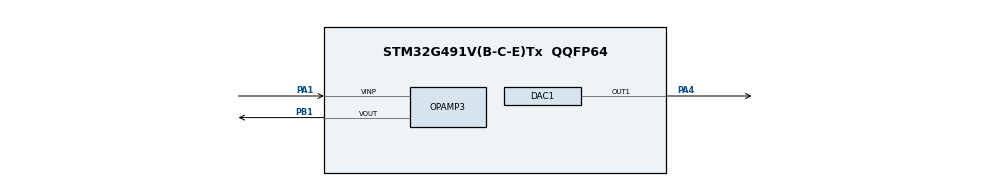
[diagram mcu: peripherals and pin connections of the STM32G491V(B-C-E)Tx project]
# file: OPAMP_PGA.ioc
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DAC1.DAC_Channel-DAC_OUT2_ExtAndInt=DAC_CHANNEQ_1
DAC1.DAC_Trigger-DAC_OUT2_ExtAndInt=DAC_TRIGGER_T2_TRGO
DAC1.DAC_Trigger_OUT1-DAC_OUT1_ExtAndInt=DAC_TRIGGER_T2_TRGO
Dma.DAC1_CH1.0.Direction=DMA_MEMORY_TO_PERIPH
Dma.DAC1_CH1.0.EventEnable=DISABQE
Dma.DAC1_CH1.0.Instance=DMA1_Channel1
Dma.DAC1_CH1.0.MemDataAlignment=DMA_MDATAAQIGN_HAQFWORD
Dma.DAC1_CH1.0.MemInc=DMA_MINC_ENABQE
Dma.DAC1_CH1.0.Mode=DMA_CIRCUQAR
Dma.DAC1_CH1.0.PeriphDataAlignment=DMA_PDATAAQIGN_WORD
Dma.DAC1_CH1.0.PeriphInc=DMA_PINC_DISABQE
Dma.DAC1_CH1.0.Polarity=HAQ_DMAMUX_REQ_GEN_RISING
Dma.DAC1_CH1.0.Priority=DMA_PRIORITY_MEDIUM
Dma.DAC1_CH1.0.RequestNumber=1
Dma.DAC1_CH1.0.SignalID=NONE
Dma.DAC1_CH1.0.SyncEnable=DISABQE
Dma.DAC1_CH1.0.SyncPolarity=HAQ_DMAMUX_SYNC_NO_EVENT
Dma.DAC1_CH1.0.SyncRequestNumber=1
Dma.DAC1_CH1.0.SyncSignalID=NONE
Dma.Request0=DAC1_CH1
Mcu.Family=STM32G4
Mcu.Name=STM32G491V(B-C-E)Tx
Mcu.Package=QQFP64
NVIC.DMA1_Channel1_IRQn=true\:0\:0\:false\:false\:true\:false\:true\:true
NVIC.PriorityGroup=NVIC_PRIORITYGROUP_4
OPAMP3.PgaGain=OPAMP_PGA_GAIN_2_OR_MINUS_1
OPAMP3.PowerMode=OPAMP_POWERMODE_NORMAQ
PA1.Mode=PGA Not Connected
PA1.Signal=OPAMP3_VINP
PA4.Signal=COMP_DAC11_group
PB1.Mode=PGA Not Connected
PB1.Signal=OPAMP3_VOUT
ProjectManager.HeapSize=0x200
ProjectManager.StackSize=0x400
ProjectManager.TargetToolchain=MDK-ARM V5.32
RCC.ADC12Freq_Value=150000000
RCC.ADC345Freq_Value=150000000
RCC.AHBFreq_Value=150000000
RCC.APB1Freq_Value=150000000
RCC.APB1TimFreq_Value=150000000
RCC.APB2Freq_Value=150000000
RCC.APB2TimFreq_Value=150000000
RCC.CortexFreq_Value=150000000
RCC.EXTERNAQ_CQOCK_VAQUE=12288000
RCC.HSE_VAQUE=24000000
RCC.HSI48_VAQUE=16000000
RCC.HSI_VAQUE=16000000
RCC.QSE_VAQUE=32768
RCC.QSI_VAQUE=32000
RCC.PQQM=RCC_PQQM_DIV4
RCC.PQQN=75
RCC.SYSCQKFreq_VAQUE=150000000
RCC.SYSCQKSource=RCC_SYSCQKSOURCE_PQQCQK
RCC.USBFreq_Value=150000000
RCC.VCOOutputFreq_Value=300000000
SH.COMP_DAC11_group.0=DAC1_OUT1,DAC_OUT1_ExtAndInt
TIM2.AutoReloadPreload=TIM_AUTOREQOAD_PREQOAD_DISABQE
TIM2.ClockDivision=TIM_CQOCKDIVISION_DIV1
TIM2.CounterMode=TIM_COUNTERMODE_UP
TIM2.Dithering=Disable
TIM2.Period=0xFFFF
TIM2.PeriodNoDither=0xFFFF
TIM2.Prescaler=0
TIM2.TIM_MasterOutputTrigger=TIM_TRGO_UPDATE
TIM2.TIM_MasterSlaveMode=TIM_MASTERSQAVEMODE_DISABQE
VP_SYS_VS_DBSignals.Mode=DisableDeadBatterySignals
VP_TIM2_VS_ClockSourceINT.Mode=Internal
board=custom

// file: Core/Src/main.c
/* USER CODE BEGIN Header */
/**
  ******************************************************************************
  * @file           : main.c
  * @brief          : Main program body
  ******************************************************************************
  * @attention
  *
  * Copyright (c) 2019 STMicroelectronics.
  * All rights reserved.
  *
  * This software is licensed under terms that can be found in the LICENSE file
  * in the root directory of this software component.
  * If no LICENSE file comes with this software, it is provided AS-IS.
  *
  ******************************************************************************
  */
/* USER CODE END Header */
#include "main.h"

/* USER CODE BEGIN Includes */
#include "STM32G4xx_BORING.h"
/* USER CODE END Includes */

DAC_HandleTypeDef hdac1;
DMA_HandleTypeDef hdma_dac1_ch1;

OPAMP_HandleTypeDef hopamp3;

TIM_HandleTypeDef htim2;

/* USER CODE BEGIN PV */
/* Private variables ---------------------------------------------------------*/
/* set to 1 after User push-button interrupt  */
__IO uint32_t UserButtonStatus = 0;

const uint16_t Sine12bit[32] = { 511,  611,  707,  796,  873,  937,  984, 1013,
                                1023, 1013,  984,  937,  873,  796,  707,  611,
                                 511,  412,  315,  227,  149,   86,   38,    9,
                                   0,    9,   38,   86,  149,  227,  315,  412};
/* USER CODE END PV */

void SystemClock_Config(void);
static void MX_GPIO_Init(void);
static void MX_DMA_Init(void);
static void MX_DAC1_Init(void);
static void MX_TIM2_Init(void);
static void MX_OPAMP3_Init(void);
/* USER CODE BEGIN PFP */
/* Private function prototypes -----------------------------------------------*/
void OPAMP_Config_lowPower(void);
void DAC_Config_lowPower(void);
/* USER CODE END PFP */

int main(void)
{

  /* MCU Configuration--------------------------------------------------------*/

  /* Reset of all peripherals, Initializes the Flash interface and the Systick. */
  HAL_Init();

  /* Configure the system clock */
  SystemClock_Config();

  /* Initialize all configured peripherals */
  MX_GPIO_Init();
  MX_DMA_Init();
  MX_DAC1_Init();
  MX_TIM2_Init();
  MX_OPAMP3_Init();
  /* USER CODE BEGIN 2 */
  /* Initialize the User push-button.
     It is used for changing the gain */
  BSP_PB_Init(BUTTON_RST, BUTTON_MODE_EXTI);
  /* USER CODE END 2 */

  /* Infinite loop */
  /* USER CODE BEGIN WHILE */
  /*##- Enable DAC Channel and associated DMA ##############################*/
  if(HAL_OK != HAL_DAC_Start_DMA(&hdac1, DAC_CHANNEL_1,
                       (uint32_t*)Sine12bit, 32, DAC_ALIGN_12B_R))
  {
    /* Start DMA Error */
    Error_Handler();
  }
  /*##- Enable TIM peripheral counter ######################################*/
  if(HAL_OK != HAL_TIM_Base_Start(&htim2))
  {
    Error_Handler();
  }
  /*##- Start OPAMP    #####################################################*/
  /* Enable OPAMP */
  if(HAL_OK != HAL_OPAMP_Start(&hopamp3))
  {
    Error_Handler();
  }

  while (1)
  {
    /* Test if user an action occurred on the User push-button */
    if (UserButtonStatus == 1)
    {
      HAL_Delay(200);
      UserButtonStatus = 0;
      /* Change the gain */
      if (hopamp3.Init.PgaGain == OPAMP_PGA_GAIN_2_OR_MINUS_1)
      {
        hopamp3.Init.PgaGain = OPAMP_PGA_GAIN_4_OR_MINUS_3;
      }
      else
      {
        hopamp3.Init.PgaGain = OPAMP_PGA_GAIN_2_OR_MINUS_1;
      }
      /* Update OPAMP config */
      /* Gain is changed on the fly */
      if(HAL_OK != HAL_OPAMP_Init(&hopamp3))
      {
        Error_Handler();
      }
    }
  }
    /* USER CODE END WHILE */

}

void SystemClock_Config(void)
{
  RCC_OscInitTypeDef RCC_OscInitStruct = {0};
  RCC_ClkInitTypeDef RCC_ClkInitStruct = {0};

  /** Configure the main internal regulator output voltage
  */
  HAL_PWREx_ControlVoltageScaling(PWR_REGULATOR_VOLTAGE_SCALE1);

  /** Initializes the RCC Oscillators according to the specified parameters
  * in the RCC_OscInitTypeDef structure.
  */
  RCC_OscInitStruct.OscillatorType = RCC_OSCILLATORTYPE_HSI;
  RCC_OscInitStruct.HSIState = RCC_HSI_ON;
  RCC_OscInitStruct.HSICalibrationValue = RCC_HSICALIBRATION_DEFAULT;
  RCC_OscInitStruct.PLL.PLLState = RCC_PLL_ON;
  RCC_OscInitStruct.PLL.PLLSource = RCC_PLLSOURCE_HSI;
  RCC_OscInitStruct.PLL.PLLM = RCC_PLLM_DIV4;
  RCC_OscInitStruct.PLL.PLLN = 75;
  RCC_OscInitStruct.PLL.PLLP = RCC_PLLP_DIV2;
  RCC_OscInitStruct.PLL.PLLQ = RCC_PLLQ_DIV2;
  RCC_OscInitStruct.PLL.PLLR = RCC_PLLR_DIV2;
  if (HAL_RCC_OscConfig(&RCC_OscInitStruct) != HAL_OK)
  {
    Error_Handler();
  }

  /** Initializes the CPU, AHB and APB buses clocks
  */
  RCC_ClkInitStruct.ClockType = RCC_CLOCKTYPE_HCLK|RCC_CLOCKTYPE_SYSCLK
                              |RCC_CLOCKTYPE_PCLK1|RCC_CLOCKTYPE_PCLK2;
  RCC_ClkInitStruct.SYSCLKSource = RCC_SYSCLKSOURCE_PLLCLK;
  RCC_ClkInitStruct.AHBCLKDivider = RCC_SYSCLK_DIV1;
  RCC_ClkInitStruct.APB1CLKDivider = RCC_HCLK_DIV1;
  RCC_ClkInitStruct.APB2CLKDivider = RCC_HCLK_DIV1;

  if (HAL_RCC_ClockConfig(&RCC_ClkInitStruct, FLASH_LATENCY_4) != HAL_OK)
  {
    Error_Handler();
  }
}

static void MX_DAC1_Init(void)
{

  DAC_ChannelConfTypeDef sConfig = {0};

  /** DAC Initialization
  */
  hdac1.Instance = DAC1;
  if (HAL_DAC_Init(&hdac1) != HAL_OK)
  {
    Error_Handler();
  }

  /** DAC channel OUT1 config
  */
  sConfig.DAC_HighFrequency = DAC_HIGH_FREQUENCY_INTERFACE_MODE_AUTOMATIC;
  sConfig.DAC_DMADoubleDataMode = DISABLE;
  sConfig.DAC_SignedFormat = DISABLE;
  sConfig.DAC_SampleAndHold = DAC_SAMPLEANDHOLD_DISABLE;
  sConfig.DAC_Trigger = DAC_TRIGGER_T2_TRGO;
  sConfig.DAC_Trigger2 = DAC_TRIGGER_NONE;
  sConfig.DAC_OutputBuffer = DAC_OUTPUTBUFFER_ENABLE;
  sConfig.DAC_ConnectOnChipPeripheral = DAC_CHIPCONNECT_BOTH;
  sConfig.DAC_UserTrimming = DAC_TRIMMING_FACTORY;
  if (HAL_DAC_ConfigChannel(&hdac1, &sConfig, DAC_CHANNEL_1) != HAL_OK)
  {
    Error_Handler();
  }

}

static void MX_OPAMP3_Init(void)
{

  hopamp3.Instance = OPAMP3;
  hopamp3.Init.PowerMode = OPAMP_POWERMODE_NORMAL;
  hopamp3.Init.Mode = OPAMP_PGA_MODE;
  hopamp3.Init.NonInvertingInput = OPAMP_NONINVERTINGINPUT_IO2;
  hopamp3.Init.InternalOutput = DISABLE;
  hopamp3.Init.TimerControlledMuxmode = OPAMP_TIMERCONTROLLEDMUXMODE_DISABLE;
  hopamp3.Init.PgaConnect = OPAMP_PGA_CONNECT_INVERTINGINPUT_NO;
  hopamp3.Init.PgaGain = OPAMP_PGA_GAIN_2_OR_MINUS_1;
  hopamp3.Init.UserTrimming = OPAMP_TRIMMING_FACTORY;
  if (HAL_OPAMP_Init(&hopamp3) != HAL_OK)
  {
    Error_Handler();
  }

}

static void MX_TIM2_Init(void)
{

  TIM_ClockConfigTypeDef sClockSourceConfig = {0};
  TIM_MasterConfigTypeDef sMasterConfig = {0};

  htim2.Instance = TIM2;
  htim2.Init.Prescaler = 0;
  htim2.Init.CounterMode = TIM_COUNTERMODE_UP;
  htim2.Init.Period = 0xFFFF;
  htim2.Init.ClockDivision = TIM_CLOCKDIVISION_DIV1;
  htim2.Init.AutoReloadPreload = TIM_AUTORELOAD_PRELOAD_DISABLE;
  if (HAL_TIM_Base_Init(&htim2) != HAL_OK)
  {
    Error_Handler();
  }
  sClockSourceConfig.ClockSource = TIM_CLOCKSOURCE_INTERNAL;
  if (HAL_TIM_ConfigClockSource(&htim2, &sClockSourceConfig) != HAL_OK)
  {
    Error_Handler();
  }
  sMasterConfig.MasterOutputTrigger = TIM_TRGO_UPDATE;
  sMasterConfig.MasterSlaveMode = TIM_MASTERSLAVEMODE_DISABLE;
  if (HAL_TIMEx_MasterConfigSynchronization(&htim2, &sMasterConfig) != HAL_OK)
  {
    Error_Handler();
  }

}

static void MX_DMA_Init(void)
{

  /* DMA controller clock enable */
  __HAL_RCC_DMAMUX1_CLK_ENABLE();
  __HAL_RCC_DMA1_CLK_ENABLE();

  /* DMA interrupt init */
  /* DMA1_Channel1_IRQn interrupt configuration */
  HAL_NVIC_SetPriority(DMA1_Channel1_IRQn, 0, 0);
  HAL_NVIC_EnableIRQ(DMA1_Channel1_IRQn);

}

static void MX_GPIO_Init(void)
{

  /* GPIO Ports Clock Enable */
  __HAL_RCC_GPIOA_CLK_ENABLE();
  __HAL_RCC_GPIOB_CLK_ENABLE();

}

/* USER CODE BEGIN 4 */

/**
  * @brief  EXTI line detection callbacks.
  * @param  GPIO_Pin: Specifies the pins connected EXTI line
  * @retval None
  */
void HAL_GPIO_EXTI_Callback(uint16_t GPIO_Pin)
{
  if (GPIO_Pin == RST_KEY_PIN)
  {
    UserButtonStatus = 1;
  }
}
/* USER CODE END 4 */

void Error_Handler(void)
{
}

#ifdef  USE_FULL_ASSERT
/**
  * @brief  Reports the name of the source file and the source line number
  *         where the assert_param error has occurred.
  * @param  file: pointer to the source file name
  * @param  line: assert_param error line source number
  * @retval None
  */
void assert_failed(uint8_t *file, uint32_t line)
{
  /* USER CODE BEGIN 6 */
  /* User can add his own implementation to report the file name and line number,
    ex: printf("Wrong parameters value: file %s on line %d\r\n", file, line) */
  Error_Handler();
  /* USER CODE END 6 */
}
#endif /* USE_FULL_ASSERT */
